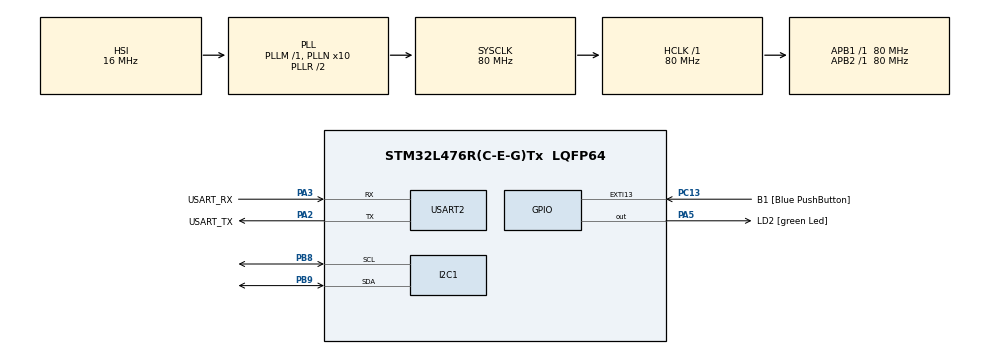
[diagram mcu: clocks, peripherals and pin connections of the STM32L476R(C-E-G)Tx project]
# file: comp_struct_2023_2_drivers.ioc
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I2C1.Timing=0x10909CEC
Mcu.Family=STM32L4
Mcu.Name=STM32L476R(C-E-G)Tx
Mcu.Package=LQFP64
NVIC.PriorityGroup=NVIC_PRIORITYGROUP_4
NVIC.USART2_IRQn=true\:0\:0\:false\:false\:true\:true\:true\:true
PA13\ (JTMS-SWDIO).GPIO_Label=TMS
PA13\ (JTMS-SWDIO).Mode=Serial_Wire
PA13\ (JTMS-SWDIO).Signal=SYS_JTMS-SWDIO
PA14\ (JTCK-SWCLK).GPIO_Label=TCK
PA14\ (JTCK-SWCLK).Mode=Serial_Wire
PA14\ (JTCK-SWCLK).Signal=SYS_JTCK-SWCLK
PA2.GPIO_Label=USART_TX
PA2.GPIO_Mode=GPIO_MODE_AF_PP
PA2.GPIO_PuPd=GPIO_NOPULL
PA2.GPIO_Speed=GPIO_SPEED_FREQ_VERY_HIGH
PA2.Mode=Asynchronous
PA2.Signal=USART2_TX
PA3.GPIO_Label=USART_RX
PA3.GPIO_Mode=GPIO_MODE_AF_PP
PA3.GPIO_PuPd=GPIO_NOPULL
PA3.GPIO_Speed=GPIO_SPEED_FREQ_VERY_HIGH
PA3.Mode=Asynchronous
PA3.Signal=USART2_RX
PA5.GPIO_Label=LD2 [green Led]
PA5.GPIO_ModeDefaultOutputPP=GPIO_MODE_OUTPUT_PP
PA5.GPIO_PuPd=GPIO_NOPULL
PA5.GPIO_Speed=GPIO_SPEED_FREQ_LOW
PA5.Signal=GPIO_Output
PB3\ (JTDO-TRACESWO).GPIO_Label=SWO
PB3\ (JTDO-TRACESWO).Signal=SYS_JTDO-SWO
PB8.Mode=I2C
PB8.Signal=I2C1_SCL
PB9.Mode=I2C
PB9.Signal=I2C1_SDA
PC13.GPIO_Label=B1 [Blue PushButton]
PC13.GPIO_ModeDefaultEXTI=GPIO_MODE_IT_FALLING
PC13.GPIO_PuPd=GPIO_NOPULL
PC13.Signal=GPXTI13
PC14-OSC32_IN\ (PC14).Mode=LSE-External-Oscillator
PC14-OSC32_IN\ (PC14).Signal=RCC_OSC32_IN
PC15-OSC32_OUT\ (PC15).Mode=LSE-External-Oscillator
PC15-OSC32_OUT\ (PC15).Signal=RCC_OSC32_OUT
PH0-OSC_IN\ (PH0).Signal=RCC_OSC_IN
PH1-OSC_OUT\ (PH1).Signal=RCC_OSC_OUT
ProjectManager.HeapSize=0x200
ProjectManager.StackSize=0x400
ProjectManager.TargetToolchain=STM32CubeIDE
RCC.ADCFreq_Value=64000000
RCC.AHBFreq_Value=80000000
RCC.APB1Freq_Value=80000000
RCC.APB1TimFreq_Value=80000000
RCC.APB2Freq_Value=80000000
RCC.APB2TimFreq_Value=80000000
RCC.CortexFreq_Value=80000000
RCC.HCLKFreq_Value=80000000
RCC.HSE_VALUE=8000000
RCC.HSI_VALUE=16000000
RCC.MSI_VALUE=4000000
RCC.PLLN=10
RCC.PLLSourceVirtual=RCC_PLLSOURCE_HSI
RCC.PREFETCH_ENABLE=1
RCC.SYSCLKFreq_VALUE=80000000
RCC.SYSCLKSource=RCC_SYSCLKSOURCE_PLLCLK
RCC.USBFreq_Value=64000000
RCC.VCOOutputFreq_Value=160000000
USART2.VirtualMode-Asynchronous=VM_ASYNC
board=NUCLEO-L476RG

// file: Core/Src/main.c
/* USER CODE BEGIN Header */
/**
  ******************************************************************************
  * @file           : main.c
  * @brief          : Main program body
  ******************************************************************************
  * @attention
  *
  * Copyright (c) 2023 STMicroelectronics.
  * All rights reserved.
  *
  * This software is licensed under terms that can be found in the LICENSE file
  * in the root directory of this software component.
  * If no LICENSE file comes with this software, it is provided AS-IS.
  *
  ******************************************************************************
  */
/* USER CODE END Header */
#include "main.h"

/* USER CODE BEGIN Includes */
#include "ring_buffer.h"
#include "keyboard.h"
#include "stdio.h"
#include "string.h"
#include "ssd1306.h"
#include "ssd1306_fonts.h"
/* USER CODE END Includes */

I2C_HandleTypeDef hi2c1;

UART_HandleTypeDef huart2;

/* USER CODE BEGIN PV */
uint16_t key_event = 0xFF;
uint8_t rx_buffer[16];
ring_buffer_t ring_buffer_uart_rx;
uint8_t rx_data;
/* USER CODE END PV */

void SystemClock_Config(void);
static void MX_GPIO_Init(void);
static void MX_USART2_UART_Init(void);
static void MX_I2C1_Init(void);

/* USER CODE BEGIN 0 */
void HAL_UART_RxCpltCallback(UART_HandleTypeDef *huart){
	ring_buffer_put(&ring_buffer_uart_rx, rx_data);
	HAL_UART_Receive_IT(&huart2, &rx_data,1);
}

int _write(int file, char *ptr, int len)
{
	HAL_UART_Transmit(&huart2, (uint8_t*)ptr, len, HAL_MAX_DELAY);
	return len;
}
void HAL_GPIO_EXTI_Callback(uint16_t GPIO_Pin)
{
	key_event=GPIO_Pin;
}

/* USER CODE END 0 */

int main(void)
{

  /* MCU Configuration--------------------------------------------------------*/

  /* Reset of all peripherals, Initializes the Flash interface and the Systick. */
  HAL_Init();

  /* Configure the system clock */
  SystemClock_Config();

  /* Initialize all configured peripherals */
  MX_GPIO_Init();
  MX_USART2_UART_Init();
  MX_I2C1_Init();
  /* USER CODE BEGIN 2 */

  // We define the size of our buffer to 5 due to the sequence
  ring_buffer_init(&ring_buffer_uart_rx, rx_buffer, 5);
  keypad_init();  // Initialize the keypad functionality
  HAL_UART_Receive_IT(&huart2, &rx_data, 1);

  ssd1306_Init(); // Initialize the screen functionality
  ssd1306_Fill(Black); // Fill the background with Black Color
  ssd1306_SetCursor(20, 20); // Set cursor to 20,20 position
  ssd1306_WriteString("Hi!",  Font_16x26, White); // Write Hi! in the screen
  ssd1306_UpdateScreen(); //Update the screen
  /* USER CODE END 2 */

  /* Infinite loop */
  /* USER CODE BEGIN WHILE */

  while (1)
  {

	 if (key_event != 0xFF) { // check if there is a event from the EXTi callback
	  		  uint8_t key_pressed = keypad_handler(key_event); // call the keypad handler
	  		  if (key_pressed != 0xFF) { //check if it is not 0xFF this likely represents either no key press or an invalid key press
	  			  printf("Key pressed: %x\r\n", key_pressed); // print the key pressed
	  			  if (key_pressed == 0x0E){ // check if the press key is equal to * then reset the ring buffer
	  				  ring_buffer_reset(&ring_buffer_uart_rx);
	  			  }
	  			  else{
					  ring_buffer_put(&ring_buffer_uart_rx, key_pressed); // Store the key pressed in the ring buffer
					  uint16_t size = ring_buffer_size(&ring_buffer_uart_rx);
					  if (size == 5){ // Check if the size of the buffer is equal to 5 so we can look at the sequence
						  uint8_t rx_data[size+1]; // rx_data is created here as a buffer to store a sequence of received data
						  memset(rx_data, 0, size + 1); // Initialize the buffer
						  for(uint16_t idx=0; idx < size; idx++){ // Iterate over the size of the buffer to store the values
						  			ring_buffer_get(&ring_buffer_uart_rx, &rx_data[idx]); // get the value from the ring buffer
						  		    printf("%02x", rx_data[idx]); // Print each byte in hexadecimal format
						  }
						  uint8_t birth_date[] = {0x00,0x03,0x08,0x04,0x0F}; // Birth date 2003/08/04 and the # symbol
						  if (memcmp(rx_data, birth_date, size) == 0){ // Check if keys pressed are equal to the birth date and the we print in the screen if the value is correct or not
							ssd1306_SetCursor(20, 20);
							ssd1306_Fill(White);
							ssd1306_WriteString("Pass!",  Font_16x26, Black);
							ssd1306_UpdateScreen();
						  }
						  else{
							ssd1306_SetCursor(20, 20);
							ssd1306_Fill(White);
							ssd1306_WriteString("Fail!",  Font_16x26, Black);
							ssd1306_UpdateScreen();
						  }
					  }
	  			  }
	  		  }
	  		  key_event = 0xFF; // clean the event
	 }
    /* USER CODE END WHILE */

  }
}

void SystemClock_Config(void)
{
  RCC_OscInitTypeDef RCC_OscInitStruct = {0};
  RCC_ClkInitTypeDef RCC_ClkInitStruct = {0};

  /** Configure the main internal regulator output voltage
  */
  if (HAL_PWREx_ControlVoltageScaling(PWR_REGULATOR_VOLTAGE_SCALE1) != HAL_OK)
  {
    Error_Handler();
  }

  /** Initializes the RCC Oscillators according to the specified parameters
  * in the RCC_OscInitTypeDef structure.
  */
  RCC_OscInitStruct.OscillatorType = RCC_OSCILLATORTYPE_HSI;
  RCC_OscInitStruct.HSIState = RCC_HSI_ON;
  RCC_OscInitStruct.HSICalibrationValue = RCC_HSICALIBRATION_DEFAULT;
  RCC_OscInitStruct.PLL.PLLState = RCC_PLL_ON;
  RCC_OscInitStruct.PLL.PLLSource = RCC_PLLSOURCE_HSI;
  RCC_OscInitStruct.PLL.PLLM = 1;
  RCC_OscInitStruct.PLL.PLLN = 10;
  RCC_OscInitStruct.PLL.PLLP = RCC_PLLP_DIV7;
  RCC_OscInitStruct.PLL.PLLQ = RCC_PLLQ_DIV2;
  RCC_OscInitStruct.PLL.PLLR = RCC_PLLR_DIV2;
  if (HAL_RCC_OscConfig(&RCC_OscInitStruct) != HAL_OK)
  {
    Error_Handler();
  }

  /** Initializes the CPU, AHB and APB buses clocks
  */
  RCC_ClkInitStruct.ClockType = RCC_CLOCKTYPE_HCLK|RCC_CLOCKTYPE_SYSCLK
                              |RCC_CLOCKTYPE_PCLK1|RCC_CLOCKTYPE_PCLK2;
  RCC_ClkInitStruct.SYSCLKSource = RCC_SYSCLKSOURCE_PLLCLK;
  RCC_ClkInitStruct.AHBCLKDivider = RCC_SYSCLK_DIV1;
  RCC_ClkInitStruct.APB1CLKDivider = RCC_HCLK_DIV1;
  RCC_ClkInitStruct.APB2CLKDivider = RCC_HCLK_DIV1;

  if (HAL_RCC_ClockConfig(&RCC_ClkInitStruct, FLASH_LATENCY_4) != HAL_OK)
  {
    Error_Handler();
  }
}

static void MX_I2C1_Init(void)
{

  hi2c1.Instance = I2C1;
  hi2c1.Init.Timing = 0x10909CEC;
  hi2c1.Init.OwnAddress1 = 0;
  hi2c1.Init.AddressingMode = I2C_ADDRESSINGMODE_7BIT;
  hi2c1.Init.DualAddressMode = I2C_DUALADDRESS_DISABLE;
  hi2c1.Init.OwnAddress2 = 0;
  hi2c1.Init.OwnAddress2Masks = I2C_OA2_NOMASK;
  hi2c1.Init.GeneralCallMode = I2C_GENERALCALL_DISABLE;
  hi2c1.Init.NoStretchMode = I2C_NOSTRETCH_DISABLE;
  if (HAL_I2C_Init(&hi2c1) != HAL_OK)
  {
    Error_Handler();
  }

  /** Configure Analogue filter
  */
  if (HAL_I2CEx_ConfigAnalogFilter(&hi2c1, I2C_ANALOGFILTER_ENABLE) != HAL_OK)
  {
    Error_Handler();
  }

  /** Configure Digital filter
  */
  if (HAL_I2CEx_ConfigDigitalFilter(&hi2c1, 0) != HAL_OK)
  {
    Error_Handler();
  }

}

static void MX_USART2_UART_Init(void)
{

  huart2.Instance = USART2;
  huart2.Init.BaudRate = 115200;
  huart2.Init.WordLength = UART_WORDLENGTH_8B;
  huart2.Init.StopBits = UART_STOPBITS_1;
  huart2.Init.Parity = UART_PARITY_NONE;
  huart2.Init.Mode = UART_MODE_TX_RX;
  huart2.Init.HwFlowCtl = UART_HWCONTROL_NONE;
  huart2.Init.OverSampling = UART_OVERSAMPLING_16;
  huart2.Init.OneBitSampling = UART_ONE_BIT_SAMPLE_DISABLE;
  huart2.AdvancedInit.AdvFeatureInit = UART_ADVFEATURE_NO_INIT;
  if (HAL_UART_Init(&huart2) != HAL_OK)
  {
    Error_Handler();
  }

}

static void MX_GPIO_Init(void)
{
  GPIO_InitTypeDef GPIO_InitStruct = {0};

  /* GPIO Ports Clock Enable */
  __HAL_RCC_GPIOC_CLK_ENABLE();
  __HAL_RCC_GPIOH_CLK_ENABLE();
  __HAL_RCC_GPIOA_CLK_ENABLE();
  __HAL_RCC_GPIOB_CLK_ENABLE();

  /*Configure GPIO pin Output Level */
  HAL_GPIO_WritePin(GPIOA, LD2_Pin|ROW_1_Pin, GPIO_PIN_RESET);

  /*Configure GPIO pin Output Level */
  HAL_GPIO_WritePin(GPIOB, ROW_2_Pin|ROW_4_Pin|ROW_3_Pin, GPIO_PIN_RESET);

  /*Configure GPIO pin : B1_Pin */
  GPIO_InitStruct.Pin = B1_Pin;
  GPIO_InitStruct.Mode = GPIO_MODE_IT_FALLING;
  GPIO_InitStruct.Pull = GPIO_NOPULL;
  HAL_GPIO_Init(B1_GPIO_Port, &GPIO_InitStruct);

  /*Configure GPIO pins : LD2_Pin ROW_1_Pin */
  GPIO_InitStruct.Pin = LD2_Pin|ROW_1_Pin;
  GPIO_InitStruct.Mode = GPIO_MODE_OUTPUT_PP;
  GPIO_InitStruct.Pull = GPIO_NOPULL;
  GPIO_InitStruct.Speed = GPIO_SPEED_FREQ_LOW;
  HAL_GPIO_Init(GPIOA, &GPIO_InitStruct);

  /*Configure GPIO pin : COLUMN_1_Pin */
  GPIO_InitStruct.Pin = COLUMN_1_Pin;
  GPIO_InitStruct.Mode = GPIO_MODE_IT_RISING;
  GPIO_InitStruct.Pull = GPIO_PULLDOWN;
  HAL_GPIO_Init(COLUMN_1_GPIO_Port, &GPIO_InitStruct);

  /*Configure GPIO pin : COLUMN_4_Pin */
  GPIO_InitStruct.Pin = COLUMN_4_Pin;
  GPIO_InitStruct.Mode = GPIO_MODE_IT_RISING;
  GPIO_InitStruct.Pull = GPIO_PULLDOWN;
  HAL_GPIO_Init(COLUMN_4_GPIO_Port, &GPIO_InitStruct);

  /*Configure GPIO pins : COLUMN_2_Pin COLUMN_3_Pin */
  GPIO_InitStruct.Pin = COLUMN_2_Pin|COLUMN_3_Pin;
  GPIO_InitStruct.Mode = GPIO_MODE_IT_RISING;
  GPIO_InitStruct.Pull = GPIO_PULLDOWN;
  HAL_GPIO_Init(GPIOA, &GPIO_InitStruct);

  /*Configure GPIO pins : ROW_2_Pin ROW_4_Pin ROW_3_Pin */
  GPIO_InitStruct.Pin = ROW_2_Pin|ROW_4_Pin|ROW_3_Pin;
  GPIO_InitStruct.Mode = GPIO_MODE_OUTPUT_PP;
  GPIO_InitStruct.Pull = GPIO_NOPULL;
  GPIO_InitStruct.Speed = GPIO_SPEED_FREQ_LOW;
  HAL_GPIO_Init(GPIOB, &GPIO_InitStruct);

  /* EXTI interrupt init*/
  HAL_NVIC_SetPriority(EXTI9_5_IRQn, 0, 0);
  HAL_NVIC_EnableIRQ(EXTI9_5_IRQn);

  HAL_NVIC_SetPriority(EXTI15_10_IRQn, 0, 0);
  HAL_NVIC_EnableIRQ(EXTI15_10_IRQn);

}

void Error_Handler(void)
{
  __disable_irq();
  while (1)
  {
  }
}
